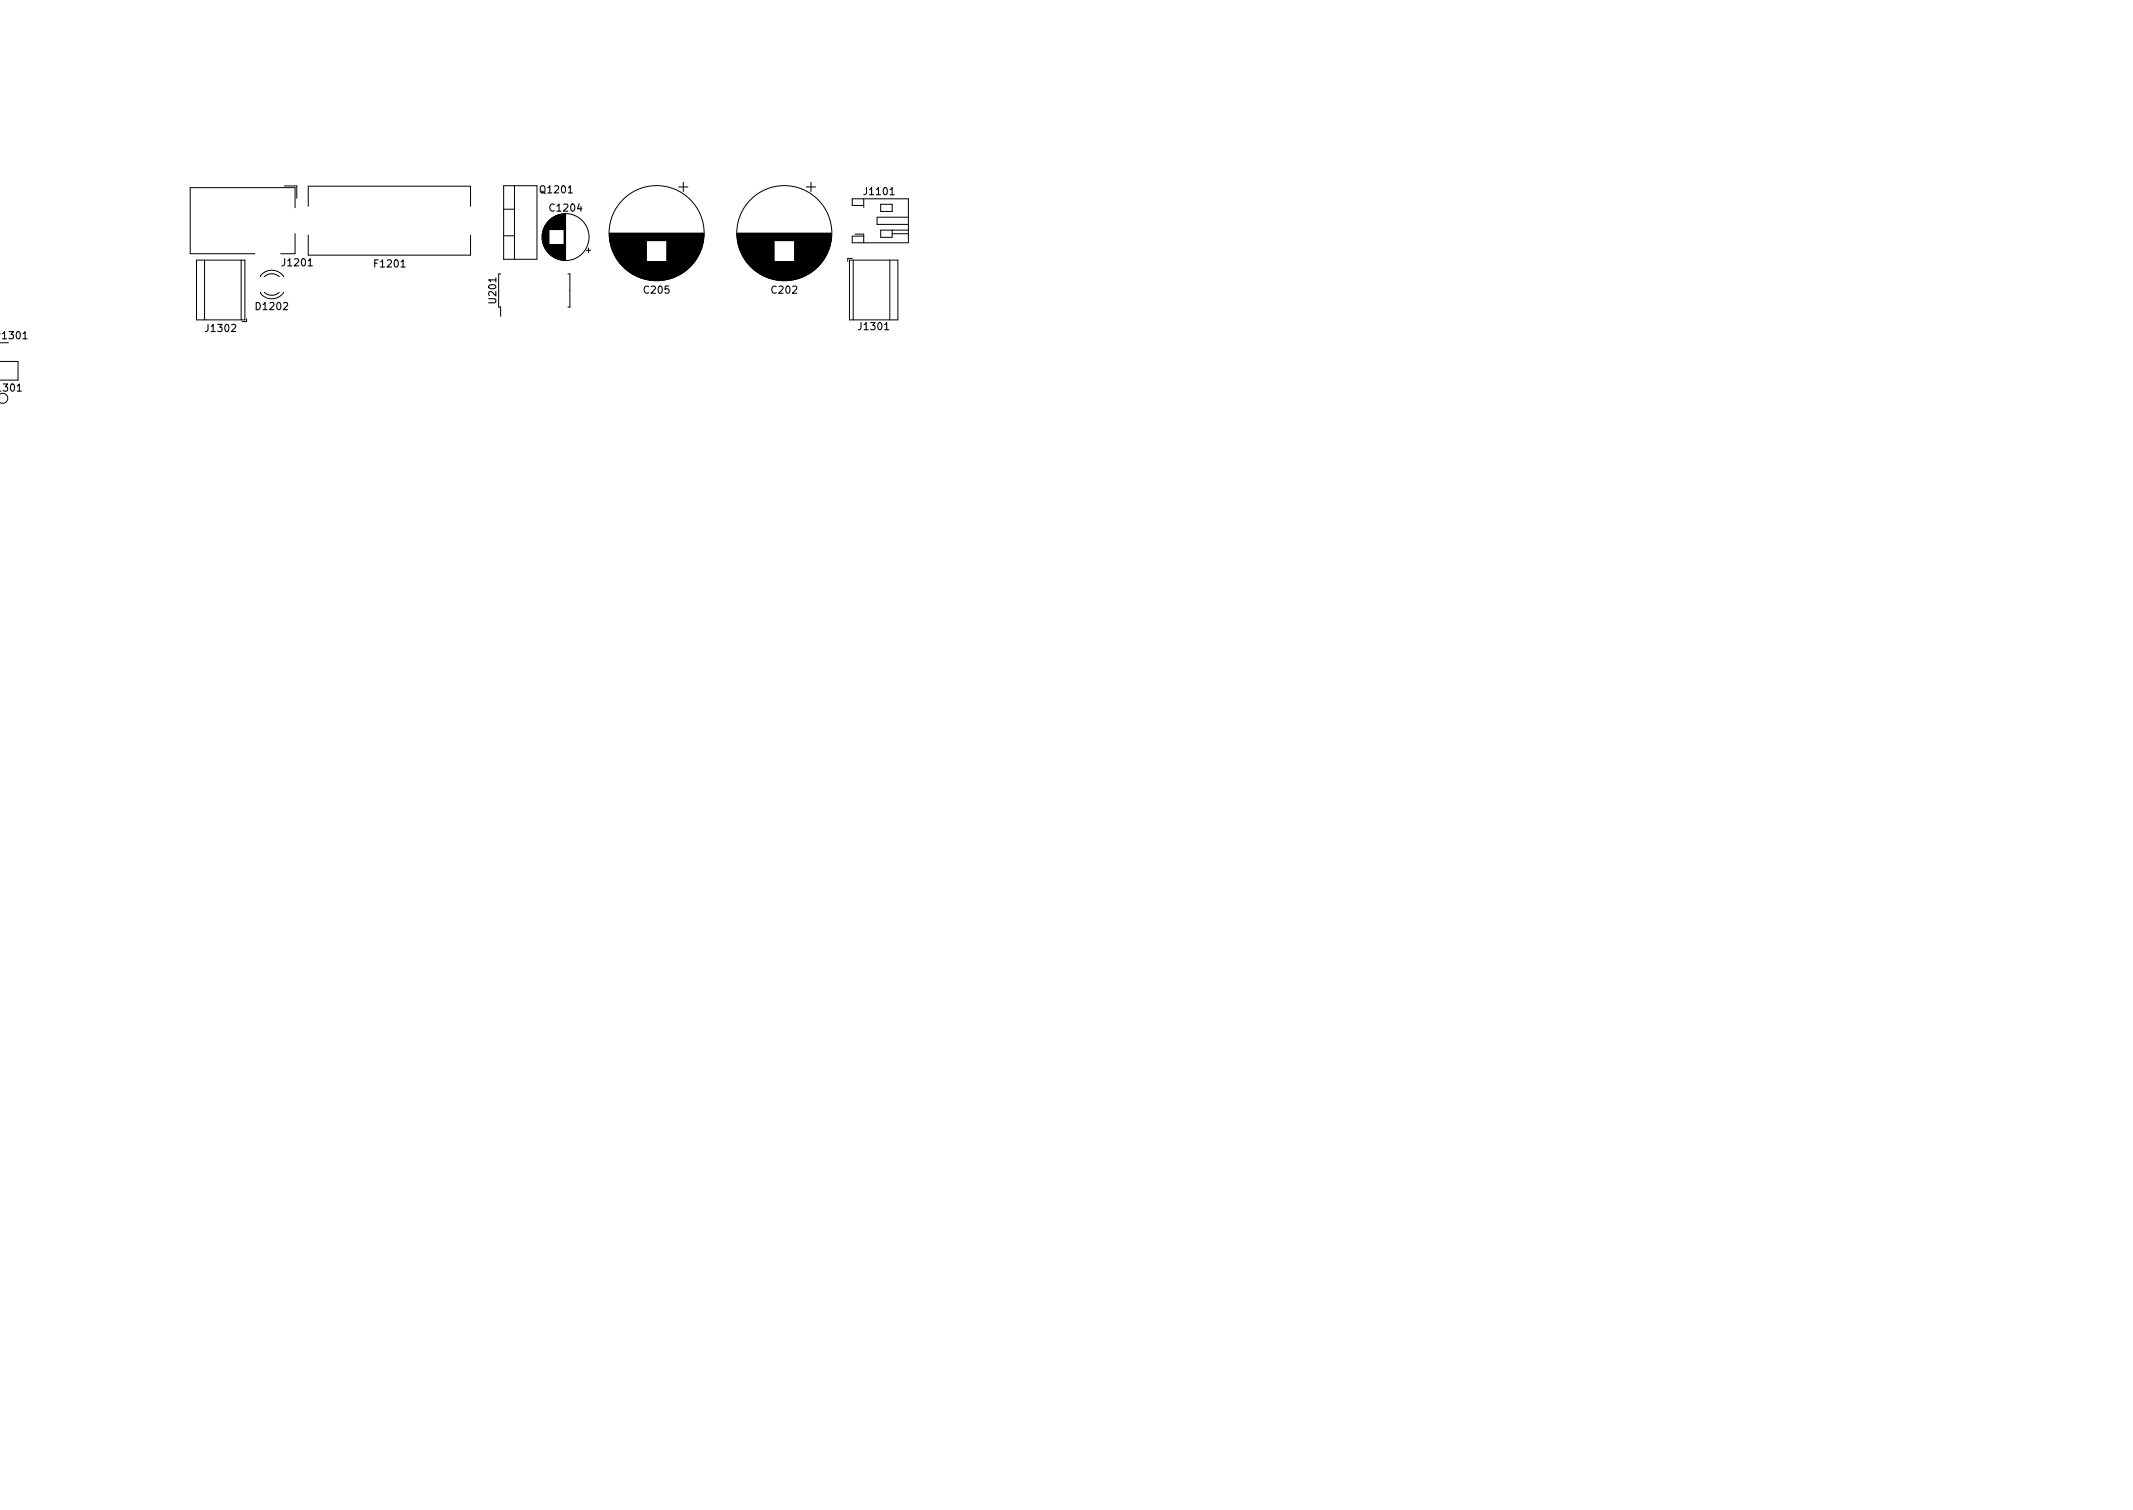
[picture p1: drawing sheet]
<svg xmlns="http://www.w3.org/2000/svg" width="297mm" height="210mm" viewBox="0 0 297 210" stroke-linecap="round" stroke-linejoin="round" font-family="sans-serif">
<defs><g id="words">
<g font-size="1.4">
<text x="75.4" y="26.9">Q1201</text>
<text x="76.7" y="29.5">C1204</text>
<text x="120.5" y="27.2">J1101</text>
<text x="39.5" y="37.1">J1201</text>
<text x="52.3" y="37.2">F1201</text>
<text x="89.8" y="40.9">C205</text>
<text x="107.6" y="40.9">C202</text>
<text x="-.4" y="47.2">P1301</text>
<text x="28.8" y="46.2">J1302</text>
<text x="35.8" y="43.2">D1202</text>
<text x="69.1" y="42.1" transform="rotate(-90 69.1 42.1)">U201</text>
<text x="119.7" y="46">J1301</text>
<text x="-.3" y="54.5">1301</text>
</g>
</g></defs>
<g fill="none" stroke="#000" stroke-width=".14">
<path d="M27.4 36.2h6.7v8.3h-6.7zM28.5 36.2v8.3M33.6 36.2v8.3M36.3 38.5a1.41 1.41 0 0 1 1.1-.8 1.99 1.99 0 0 1 2.1 .8M36.8 38.5a1.5 1.5 0 0 1 2.1 0M39.6 25.9h1.7v1.7M41.1 28.9v-2.8h-14.6v9.2h9M41.1 32.5v2.8h-2M42.9 32.7v2.8h22.6v-2.8M42.9 28.7v-2.8h22.6v2.8M69.7 38.1h-.3v4.7h.3v1.2M70.1 25.9h4.7v10.2h-4.7z"/>
<path d="M70.1 32.8h1.5M70.1 29.1h1.5M71.6 25.9v10.2M75.5 32.6v.8M75.6 32.4v1.2M75.6 32.2v1.6M75.6 32.1v1.9M75.7 32v2.1M75.7 31.8v2.4M75.8 31.8v2.5M75.8 31.7v2.7M75.8 31.6v2.8"/>
<path d="M75.9 31.5v3M75.9 31.4v3.2M76 31.4v3.3M76 31.3v3.4M76 31.2v3.6M76.1 31.2v3.6M76.1 31.1v3.8M76.2 31.1v3.9M76.2 31v4M76.2 31v4.1M76.3 30.9v4.2M76.3 30.9v4.3"/>
<path d="M76.4 30.8v4.4M76.4 30.7v4.6M76.5 30.7v1.3M76.5 34.1v1.2M76.5 34.1v1.3M76.6 30.6v1.4M76.6 34.1v1.3M76.6 34.1v1.4M76.7 30.5v1.5M76.7 34.1v1.4M76.8 30.5v1.5M76.8 34.1v1.5"/>
<path d="M76.8 30.4v1.6M76.9 30.4v1.6M76.9 34.1v1.6M77 30.3v1.7M77 34.1v1.6M77 34.1v1.7M77.1 30.2v1.8M77.1 34.1v1.7M77.2 30.2v1.8M77.2 34.1v1.7M77.2 34.1v1.8M77.3 30.1v1.9"/>
<path d="M77.3 34.1v1.8M77.4 30.1v1.9M77.4 34.1v1.8M77.4 34.1v1.9M77.5 30v2M77.5 34.1v1.9M77.6 30v2M77.6 34.1v1.9M77.7 30v2M77.7 34.1v2M77.8 29.9v2.1M77.8 34.1v2"/>
<path d="M77.9 29.9v2.1M77.9 34.1v2M78 29.9v2.1M78 34.1v2M78 34.1v2.1M78.1 29.9v2.1M78.1 34.1v2.1M78.1 29.8v2.2M78.2 29.8v2.2M78.2 34.1v2.1M78.3 29.8v2.2M78.3 34.1v2.1"/>
<path d="M78.4 29.8v2.2M78.4 34.1v2.1M78.5 29.8v2.2M78.5 34.1v2.1M78.6 29.8v6.4M78.7 29.8v6.4M78.8 29.8v6.4M79.1 38.1h.3v4.7h-.3M81.6 34.9h.7M81.9 34.5v.7M84.9 32.5h13.1M84.9 32.6h13.1"/>
<path d="M84.9 32.7h13.1M84.9 32.8h13.1M84.9 32.9h13.1M84.9 33h13.1M84.9 33.1h13.1M84.9 33.2h13.1M84.9 33.3h13.1M84.9 33.4h13.1M84.9 33.5h13M84.9 33.5h5.1M85 33.6h5M85 33.7h5"/>
<path d="M85 33.8h5M85 33.9h5M85 34h5M85.1 34.1h4.9M85.1 34.2h4.9M85.1 34.3h4.9M85.1 34.4h4.9M85.2 34.4h4.8M85.2 34.5h4.8M85.2 34.6h4.8M85.2 34.7h4.8M85.3 34.7h4.7"/>
<path d="M85.3 34.8h4.7M85.3 34.9h4.7M85.4 35h4.6M85.4 35.1h4.6M85.4 35.2h4.6M85.5 35.2h4.5M85.5 35.3h4.5M85.5 35.4h4.5M85.6 35.4h4.4M85.6 35.5h4.4M85.6 35.6h4.4M85.7 35.6h4.3"/>
<path d="M85.7 35.7h4.3M85.8 35.8h4.2M85.8 35.9h4.2M85.9 36h4.1M85.9 36.1h4.1M86 36.1h4M86 36.2h4M86.1 36.3h3.9M86.1 36.4h3.9M86.2 36.4h10.5M86.2 36.5h10.5M86.2 36.5h10.4"/>
<path d="M86.3 36.5h10.3M86.3 36.6h10.3M86.3 36.6h10.2M86.4 36.7h10.1M86.5 36.8h9.9M86.5 36.9h9.8M86.6 36.9h9.7M86.6 37h9.6M86.7 37h9.5M86.7 37.1h9.5M86.8 37.1h9.3M86.8 37.2h9.2"/>
<path d="M86.9 37.2h9.1M86.9 37.3h9.1M87 37.3h8.9M87.1 37.4h8.7M87.1 37.5h8.6M87.2 37.5h8.5M87.2 37.5h8.4M87.3 37.6h8.3M87.3 37.6h8.2M87.4 37.7h8.1M87.4 37.7h8M87.5 37.7h7.9"/>
<path d="M87.5 37.8h7.8M87.6 37.8h7.7M87.7 37.9h7.5M87.8 37.9h7.3M87.8 38h7.3M87.9 38h7.1M87.9 38.1h7M88 38.1h6.9M88.1 38.1h6.7M88.1 38.2h6.6M88.2 38.2h6.5M88.3 38.3h6.3"/>
<path d="M88.4 38.3h6.1M88.4 38.3h6M88.5 38.4h5.9M88.6 38.4h5.7M88.7 38.5h5.5M88.8 38.5h5.3M88.9 38.5h5.1M89 38.6h4.9M89.1 38.6h4.7M89.2 38.7h4.5M89.3 38.7h4.3M89.4 38.7h4.1"/>
<path d="M89.5 38.8h3.9M89.6 38.8h3.6M89.8 38.9h3.3M89.9 38.9h3M90.1 38.9h2.7M90.3 39h2.2M90.6 39h1.7M91 39.1h.9M92.9 35.9h4.1M92.9 36.4h3.8M92.9 36.3h3.9M92.9 36.2h3.9"/>
<path d="M92.9 36.2h4M92.9 36.1h4M92.9 36.1h4.1M92.9 36h4.1M92.9 35.9h4.2M92.9 35.8h4.2M92.9 35.7h4.3M92.9 35.6h4.3M92.9 35.5h4.4M92.9 35.4h4.4M92.9 35.3h4.5M92.9 35.2h4.5"/>
<path d="M92.9 35.1h4.6M92.9 35h4.6M92.9 34.9h4.6M92.9 34.9h4.7M92.9 34.8h4.7M92.9 34.7h4.7M92.9 34.6h4.8M92.9 34.5h4.8M92.9 34.4h4.8M92.9 34.3h4.8M92.9 34.3h4.9M92.9 34.2h4.9"/>
<path d="M92.9 34.1h4.9M92.9 34h4.9M92.9 33.9h5M92.9 33.8h5M92.9 33.7h5M92.9 33.6h5M92.9 33.5h5M94.5 26h1.3M95.2 25.4v1.3M102.6 32.5h13.2M102.6 32.6h13.2M102.6 32.7h13.2"/>
<path d="M102.6 32.8h13.2M102.7 32.9h13.1M102.7 33h13.1M102.7 33.1h13.1M102.7 33.2h13.1M102.7 33.3h13.1M102.7 33.3h13M102.7 33.4h13M102.7 33.5h13M102.7 33.5h5.1M102.7 33.6h5.1M102.7 33.7h5.1"/>
<path d="M102.8 33.7h5M102.8 33.8h5M102.8 33.9h5M102.8 34h5M102.8 34.1h5M102.9 34.1h4.9M102.9 34.2h4.9M102.9 34.3h4.9M102.9 34.4h4.9M102.9 34.5h4.9M103 34.5h4.8M103 34.6h4.8"/>
<path d="M103 34.7h4.8M103.1 34.8h4.7M103.1 34.9h4.7M103.1 35h4.7M103.2 35h4.6M103.2 35.1h4.6M103.2 35.2h4.6M103.3 35.3h4.5M103.3 35.4h4.5M103.4 35.5h4.4M103.4 35.6h4.4M103.5 35.7h4.3"/>
<path d="M103.5 35.8h4.3M103.6 35.8h4.2M103.6 35.9h4.2M103.7 36h4.1M103.7 36.1h4.1M103.8 36.1h4M103.8 36.2h4M103.8 36.3h4M103.9 36.3h3.9M103.9 36.4h3.9M104 36.4h10.5M104 36.5h10.5"/>
<path d="M104 36.5h10.4M104.1 36.6h10.3M104.1 36.6h10.2M104.1 36.7h10.2M104.2 36.7h10.1M104.2 36.7h10M104.2 36.8h10M104.3 36.8h9.9M104.3 36.9h9.8M104.4 36.9h9.7M104.4 37h9.6M104.5 37h9.5"/>
<path d="M104.5 37.1h9.4M104.6 37.1h9.3M104.6 37.2h9.2M104.7 37.2h9.1M104.7 37.3h9M104.8 37.3h8.9M104.8 37.4h8.8M104.9 37.4h8.7M104.9 37.5h8.6M105 37.5h8.5M105 37.5h8.4M105.1 37.6h8.3"/>
<path d="M105.1 37.6h8.2M105.2 37.7h8.1M105.2 37.7h8M105.3 37.7h7.9M105.3 37.8h7.8M105.4 37.8h7.7M105.4 37.9h7.6M105.5 37.9h7.5M105.5 37.9h7.4M105.6 38h7.2M105.7 38h7.1M105.7 38.1h7"/>
<path d="M105.8 38.1h6.8M105.9 38.1h6.7M105.9 38.2h6.6M106 38.2h6.4M106.1 38.3h6.3M106.1 38.3h6.2M106.2 38.3h6M106.3 38.4h5.8M106.4 38.4h5.7M106.5 38.5h5.5M106.5 38.5h5.4M106.6 38.5h5.2"/>
<path d="M106.7 38.6h5M106.8 38.6h4.8M106.9 38.7h4.6M107 38.7h4.4M107.2 38.7h4.1M107.3 38.8h3.9M107.4 38.8h3.6M107.6 38.9h3.3M107.7 38.9h3M107.9 38.9h2.6M108.1 39h2.2M108.4 39h1.7"/>
<path d="M108.7 39.1h1M110.7 35.9h4.1M110.7 36.4h3.8M110.7 36.3h3.8M110.7 36.3h3.9M110.7 36.2h3.9M110.7 36.2h4M110.7 36.1h4M110.7 36h4.1M110.7 35.9h4.2M110.7 35.8h4.2M110.7 35.7h4.2"/>
<path d="M110.7 35.7h4.3M110.7 35.6h4.3M110.7 35.5h4.3M110.7 35.5h4.4M110.7 35.4h4.4M110.7 35.3h4.4M110.7 35.3h4.5M110.7 35.2h4.5M110.7 35.1h4.5M110.7 35.1h4.6M110.7 35h4.6M110.7 34.9h4.6"/>
<path d="M110.7 34.9h4.7M110.7 34.8h4.7M110.7 34.7h4.7M110.7 34.6h4.7M110.7 34.6h4.8M110.7 34.5h4.8M110.7 34.4h4.8M110.7 34.3h4.8M110.7 34.3h4.9M110.7 34.2h4.9M110.7 34.1h4.9M110.7 34h4.9"/>
<path d="M110.7 33.9h4.9M110.7 33.9h5M110.7 33.8h5M110.7 33.7h5M110.7 33.6h5M110.7 33.5h5M112.3 26h1.3M112.9 25.4v1.3M118.3 36.2h6.7v8.3h-6.7zM118.7 36h-.6v.4M118.8 36.2v8.3M119.1 32.6h1.2v1.2"/>
<path d="M120.3 28.6h-1.6v-.9h7.8v6.1h-7.8v-.9h1.6M120.3 27.7v1.2M122.6 28.4h1.6v1h-1.6zM123.9 36.2v8.3M124.2 32v1h-1.6v-1h3.9M124.2 32.5h2.3M126.5 30.2h-4.4v1h4.4M-.1 54.9a.69 .69 0 0 1 1 .1 .69 .69 0 0 1 0 .9 .69 .69 0 0 1-1 .1M-.1 50.3h2.6v2.6h-2.6M34.3 44.4v.4h-.6M38.9 40.7a1.5 1.5 0 0 1-2.1 0M39.5 40.7a1.99 1.99 0 0 1-3.2 .2v-.2"/>
<circle cx="78.8" cy="33" r="3.3"/>
<circle cx="91.4" cy="32.5" r="6.6"/>
<circle cx="109.2" cy="32.5" r="6.6"/>
</g>
<use href="#words"/>
</svg>
